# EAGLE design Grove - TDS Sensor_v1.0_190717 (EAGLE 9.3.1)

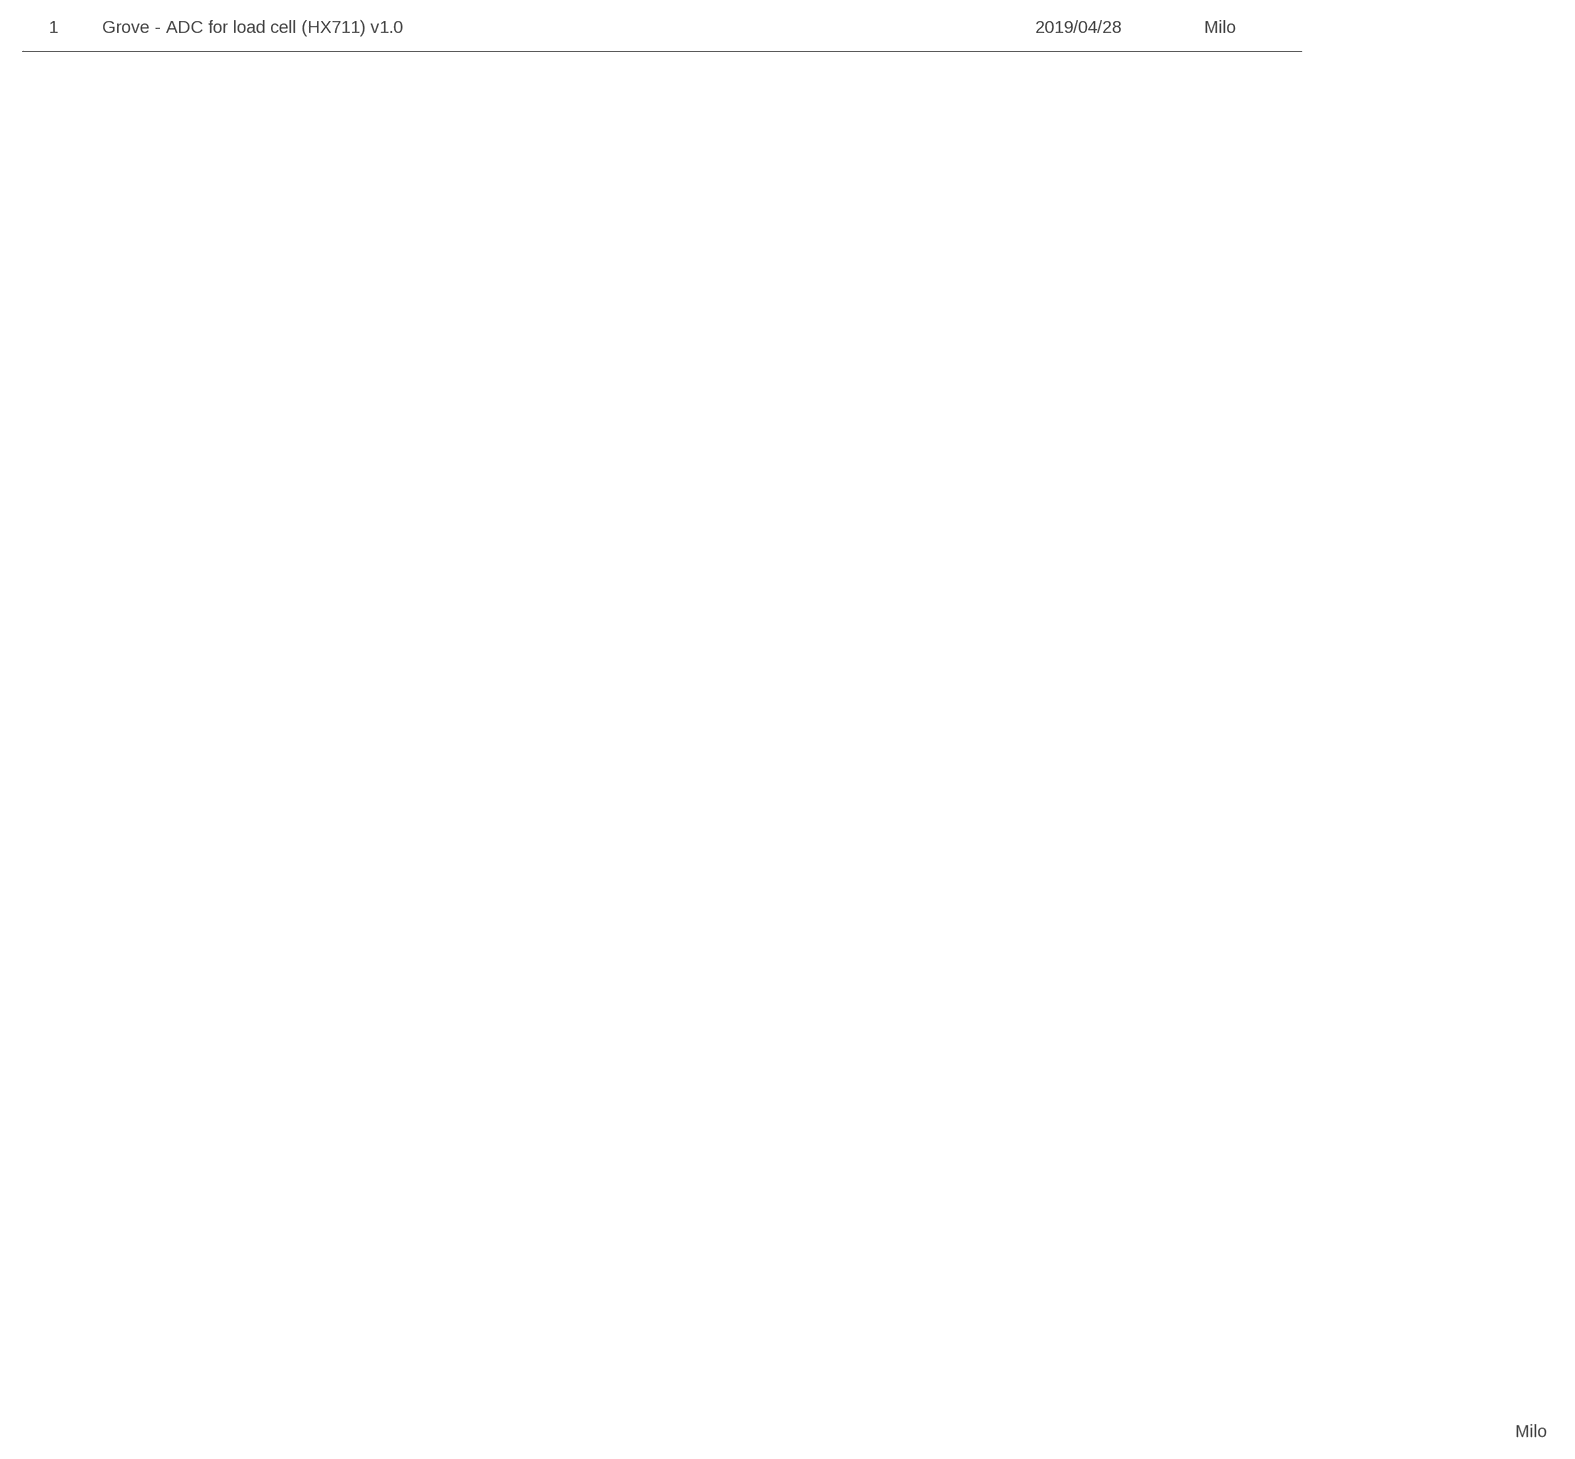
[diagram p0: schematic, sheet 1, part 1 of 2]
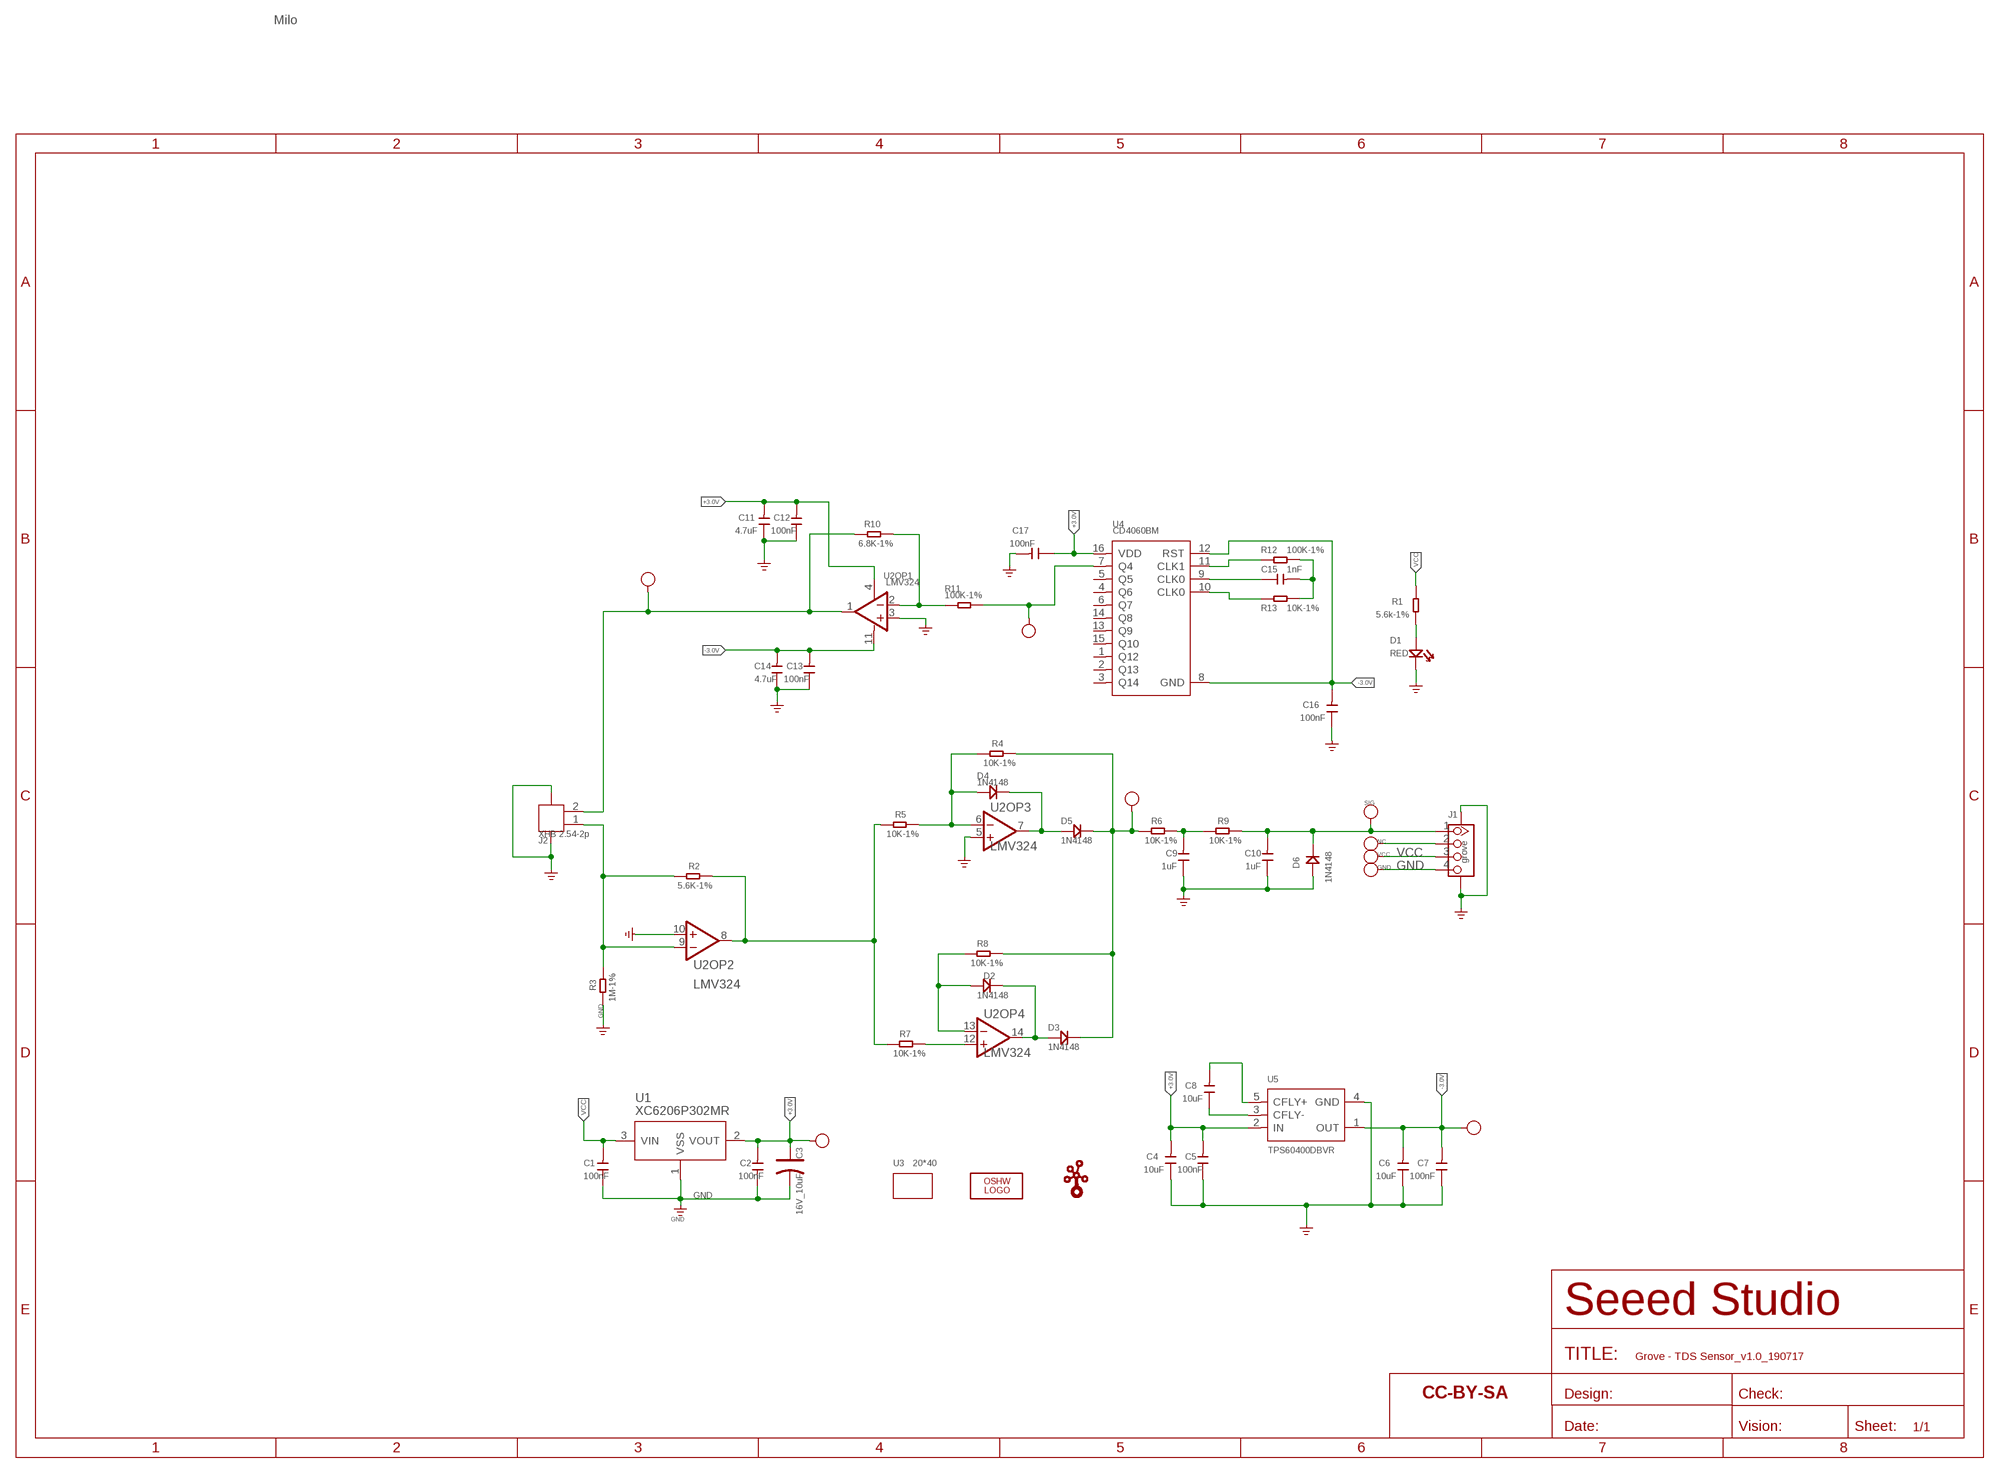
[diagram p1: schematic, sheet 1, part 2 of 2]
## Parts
+3.0V  +3.0V  PAD-TEST-POINT'4545'  [TP_4545]
-3.0V  TP2  PAD-TEST-POINT'4545'  [TP_4545]
C1  100nF  CAP-0402  [C0402]
C2  100nF  CAP-0402  [C0402]
C3  16V_10uF  CAP-POLAR-AVX-A  [AVX-A]
C4  10uF  CAP-0402  [C0402]
C5  100nF  CAP-0402  [C0402]
C6  10uF  CAP-0402  [C0402]
C7  100nF  CAP-0402  [C0402]
C8  10uF  CAP-0402  [C0402]
C9  1uF  CAP-0402  [C0402]
C10  1uF  CAP-0402  [C0402]
C11  4.7uF  CAP-0402  [C0402]
C12  100nF  CAP-0402  [C0402]
C13  100nF  CAP-0402  [C0402]
C14  4.7uF  CAP-0402  [C0402]
C15  1nF  CAP-0402  [C0402]
C16  100nF  CAP-0402  [C0402]
C17  100nF  CAP-0402  [C0402]
D1  RED  LED-0402  [LED-0402]
D2  1N4148  DIODE'0603'  [SOD-523]
D3  1N4148  DIODE'0603'  [SOD-523]
D4  1N4148  DIODE'0603'  [SOD-523]
D5  1N4148  DIODE'0603'  [SOD-523]
D6  1N4148  DIODE'0603'  [SOD-523]
GND  DNP  PAD-TEST-POINT'4545'  [TP_4545]
J1  grove  GROVE-CONNECTOR-SMD-320110030  [HW4-SMD-2.0]
J2  XHB 2.54-2p  JST-2P-SMD-2.5  [HW2-SMD-2.5-10X10X6MM]
LOGO1  LOGO-OSHW-FILLX0150-NT  [OSHW_FILLX150_NOTEXT]
NC  DNP  PAD-TEST-POINT'4545'  [TP_4545]
R1  5.6k-1%  RES-0402  [R0402]
R2  5.6K-1%  RES-0402  [R0402]
R3  1M-1%  RES-0402  [R0402]
R4  10K-1%  RES-0402  [R0402]
R5  10K-1%  RES-0402  [R0402]
R6  10K-1%  RES-0402  [R0402]
R7  10K-1%  RES-0402  [R0402]
R8  10K-1%  RES-0402  [R0402]
R9  10K-1%  RES-0402  [R0402]
R10  6.8K-1%  RES-0402  [R0402]
R11  100K-1%  RES-0402  [R0402]
R12  100K-1%  RES-0402  [R0402]
R13  10K-1%  RES-0402  [R0402]
SIG  DNP  PAD-TEST-POINT'4545'  [TP_4545]
TP3  TP2  PAD-TEST-POINT'4545'  [TP_4545]
TP4  TP2  PAD-TEST-POINT'4545'  [TP_4545]
TP5  TP2  PAD-TEST-POINT'4545'  [TP_4545]
U1  XC6206P302MR  XC6206MR  [SOT23]
U2  LMV324  AMPLIFIER-LMV324-310020019  [SOIC14-1.27-9.3X4.3MM]
U3  20*40  GROVE-1X2-TOP  [GROVE-1*2-TEST-PLATFORM-TOP]
U4  CD4060BM  CONTROLLER-CD4060BM  [SOIC16-1.27-10X3.9MM]
U5  TPS60400DBVR  PMIC-TPS60400DBVR  [SOT-23-5]
U$2  LOGO-GROVE  [GROVE-SILK-BIG]
VCC  DNP  PAD-TEST-POINT'4545'  [TP_4545]

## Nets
+3.0V: +3.0V.T C2.2 C3.+ C4.2 C5.2 C11.2 C12.2 C17.1 U1.2(VOUT) U2.4(OP1:V+) U4.16(VDD) U5.2(IN)
-3.0V: -3.0V.T C6.2 C7.2 C13.2 C14.2 C16.2 U2.11(OP1:V-) U4.8(GND) U4.12(RST) U5.1(OUT)
GND: C1.1 C2.1 C3.- C4.1 C5.1 C6.1 C7.1 C9.1 C10.1 C11.1 C12.1 C13.1 C14.1 C16.1 C17.2 D1.- D6.+ GND.T J1.4 J1.SS1 J1.SS2 J2.3 J2.4 R3.2 U1.1(VSS) U2.3(OP1:IN+) U2.5(OP3:IN+) U2.10(OP2:IN+) U5.4(GND) ; supply symbol labelled GND_POWER
N$1: D1.+ R1.1
N$2: J2.1 R2.2 R3.1 U2.9(OP2:IN-)
N$3: D4.+ R4.2 R5.1 U2.6(OP3:IN-)
N$4: D3.- D5.- R4.1 R6.1 R8.2 TP5.T
N$5: J1.2 NC.T
N$6: C9.2 R6.2 R9.2
N$7: D4.- D5.+ U2.7(OP3:OUT)
N$8: R7.2 U2.12(OP4:IN+)
N$9: D2.+ R8.1 U2.13(OP4:IN-)
N$10: D2.- D3.+ U2.14(OP4:OUT)
N$11: R10.1 R11.1 U2.2(OP1:IN-)
N$12: R2.1 R5.2 R7.1 U2.8(OP2:OUT)
N$13: J2.2 R10.2 TP4.T U2.1(OP1:OUT)
N$14: C10.2 D6.- J1.1 R9.1 SIG.T
N$15: C8.1 U5.3(CFLY-)
N$16: C8.2 U5.5(CFLY+)
N$17: R12.1 U4.11(CLK1)
N$18: C15.1 U4.9(CLK0)
N$19: R13.1 U4.10(CLK0)
N$20: C15.2 R12.2 R13.2
N$21: R11.2 TP3.T U4.7(Q4)
VCC: C1.2 J1.3 R1.2 U1.3(VIN) VCC.T
Unconnected: U4.1(Q12) U4.2(Q13) U4.3(Q14) U4.4(Q6) U4.5(Q5) U4.6(Q7) U4.13(Q9) U4.14(Q8) U4.15(Q10)

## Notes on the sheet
- 1 | Grove - ADC for load cell (HX711) v1.0 | 2019/04/28 | Milo
- Milo
- Milo

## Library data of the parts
+3.0V -3.0V GND NC SIG TP3-TP5 VCC = Discrete:PAD-TEST-POINT; PARTNO: DNP
C1 C2 C4-C17 = Discrete-new:CAP: Ceramic Capacitors
C3 = Discrete-new:CAP-POLAR: Electrolytic Capacitors,Tantalum Capacitors and Super Capacitors
D1 = Discrete-new:LED
D2-D6 = Discrete-new:DIODE
J1 = Connector-new:GROVE-CONNECTOR-SMD
J2 = Connector-new:JST-2P-SMD
LOGO1 = logo:LOGO-OSHW-FILL; PARTNO: DNP
R1-R13 = Discrete-new:RES
U1 = IC:XC6206: LOW ESR Cap.Compatible Positive Voltage Regulators
U2 = IC-new:AMPLIFIER-LMV324
U3 = moudle-new:GROVE
U4 = IC-new:CONTROLLER-CD4060BM
U5 = IC-new:PMIC-TPS60400DBVR
U$2 = logo:LOGO-GROVE; PARTNO: DNP

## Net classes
3 usbvcc: width 0.508 mm, drill 0.61 mm, clearance 0.254 mm

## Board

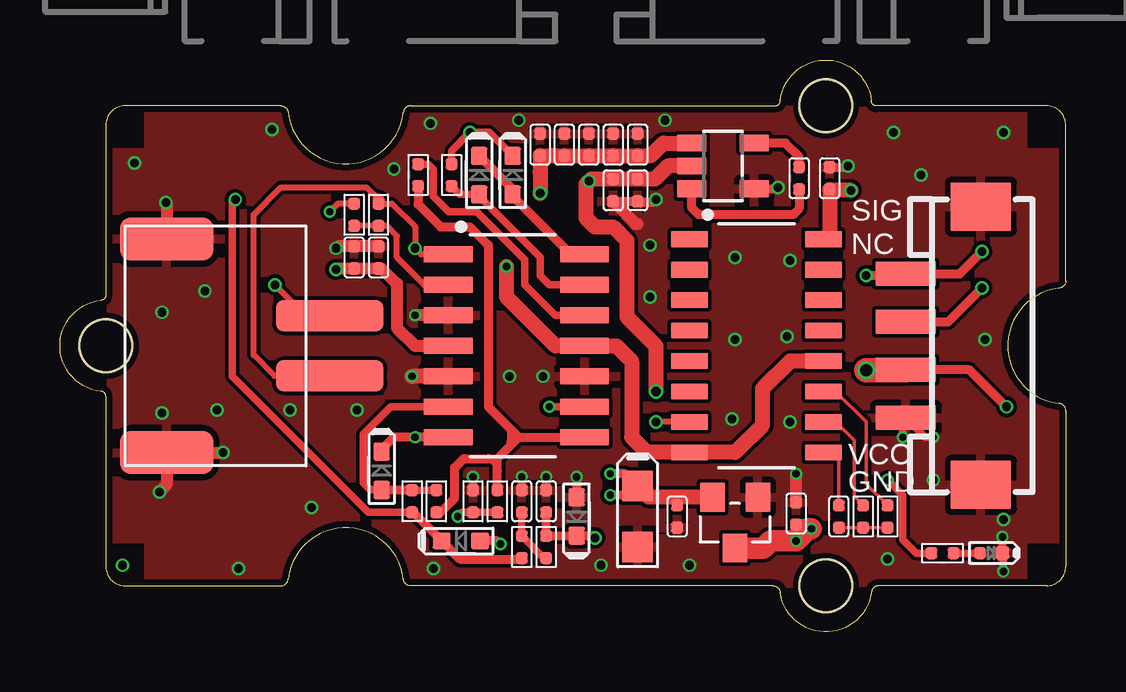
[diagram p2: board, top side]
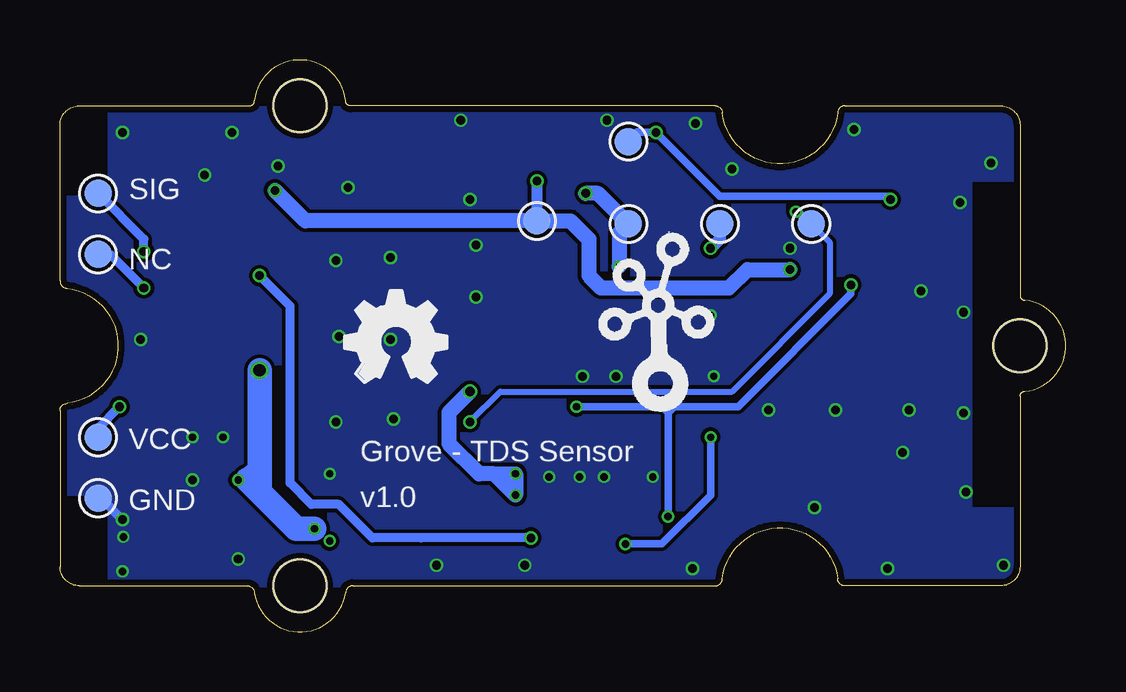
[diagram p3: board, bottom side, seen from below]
Size 41.91 x 23.83 mm. Coordinates in mm from the lower left corner, seen from the top.
Copper layers (1*16): Top 0.035mm / dielectric 1.5mm / Bottom 0.035mm
Design rules "SeeedStudio_2layer_DRU_no_angle_20140221": minimum track width 1mil, minimum drill 10mil, track to track 6mil, track to pad 6mil, pad to pad 6mil, via to via 6mil, smd to smd 0mil, copper to edge 10mil, drill to drill 10mil, minimum pad ring 4mil, minimum via ring 4mil, stop-mask expansion 2mil, vias tented up to drill 25mil, thermal gap 10mil

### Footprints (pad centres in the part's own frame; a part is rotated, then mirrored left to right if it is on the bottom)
TP_4545 = smd 1.143 x 1.143: T 0,0
C0402 = smd 0.5 x 0.5: 1 -0.463,0; 2 0.463,0
AVX-A = smd 1.27 x 1.27: + 1.27,0; - -1.27,0
LED-0402 = smd 0.5 x 0.5: + 0.463,0 | smd 0.58 x 0.58: - -0.468,0
SOD-523 = smd 0.762 x 0.7: + 0.8,0; - -0.8,0
HW4-SMD-2.0 = smd 1 x 2.5: 1 -3,0; 2 -1,0; 3 1,0; 4 3,0 | smd 2 x 2.5: SS1 -5.8,3.123; SS2 5.8,3.123
HW2-SMD-2.5-10X10X6MM = smd 1.3 x 4.5: 1 -1.25,0; 2 1.25,0 | smd 1.8 x 3.9: 3 -4.45,-6.8; 4 4.45,-6.8
R0402 = smd 0.5 x 0.5: 1 -0.463,0; 2 0.463,0
SOT23 = smd 1.016 x 1.2: 1 -0.95,-1.06; 2 0.95,-1.06; 3 0,1.06
SOIC14-1.27-9.3X4.3MM = smd 0.66 x 2.032: 1 -3.81,-2.68; 2 -2.54,-2.68; 3 -1.27,-2.68; 4 0,-2.68; 5 1.27,-2.68; 6 2.54,-2.68; 7 3.81,-2.68; 8 3.81,2.997; 9 2.54,2.997; 10 1.27,2.997; 11 0,2.997; 12 -1.27,2.997; 13 -2.54,2.997; 14 -3.81,2.997
GROVE-1*2-TEST-PLATFORM-TOP = hole 2.2: 10.635,10; 10.635,-10; -19.365,0
SOIC16-1.27-10X3.9MM = smd 0.66 x 1.524: 1 -4.445,-2.794; 2 -3.175,-2.794; 3 -1.905,-2.794; 4 -0.635,-2.794; 5 0.635,-2.794; 6 1.905,-2.794; 7 3.175,-2.794; 8 4.445,-2.794; 9 4.445,2.794; 10 3.175,2.794; 11 1.905,2.794; 12 0.635,2.794; 13 -0.635,2.794; 14 -1.905,2.794; 15 -3.175,2.794; 16 -4.445,2.794
SOT-23-5 = smd 0.69 x 1.2: 1 -0.95,-1.3; 2 0,-1.3; 3 0.95,-1.3; 4 0.95,1.3; 5 -0.95,1.3

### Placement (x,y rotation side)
+3.0V  22.04,17.13 0 bottom
-3.0V  18.23,17 0 bottom
C1  30.67,4.94 270 top
C2  25.72,4.81 90 top
C3  24.07,4.81 90 top
C4  23.05,18.4 90 top
C5  24.07,18.4 90 top
C6  23.05,20.3 270 top
C7  24.07,20.3 270 top
C8  30.8,18.91 90 top
C9  19.24,5.44 270 top
C10  20.26,5.44 270 top
C11  12.26,15.6 270 top
C12  32.07,18.91 270 top
C13  21.02,20.3 270 top
C14  20,20.3 270 top
C15  32.45,4.81 270 top
C16  22.04,20.3 270 top
C17  13.27,15.6 90 top
D1  38.8,3.29 180 top
D2  17.46,19.03 270 top
D3  18.86,19.03 270 top
D4  13.4,6.71 270 top
D5  16.7,3.79 0 top
D6  21.53,4.81 90 top
GND  40.32,5.57 0 bottom
J1  35.24,11.92 270 top
J2  11.24,11.92 270 top
LOGO1  30.04,10.4 0 bottom
NC  40.32,15.73 0 bottom
R1  36.77,3.29 180 top
R2  18.23,5.44 270 top
R3  17.21,5.44 90 top
R4  14.67,5.44 90 top
R5  15.69,5.44 270 top
R6  19.24,3.54 90 top
R7  14.92,19.03 90 top
R8  16.32,19.03 90 top
R9  20.26,3.54 270 top
R10  13.27,17.38 90 top
R11  12.26,17.38 90 top
R12  34.48,4.81 270 top
R13  33.47,4.81 270 top
SIG  40.32,18.27 0 bottom
TP3  10.61,17 0 bottom
TP4  14.42,17 0 bottom
TP5  18.23,20.43 0 bottom
U1  28.13,4.56 180 top
U2  18.86,11.92 270 top
U3  21.27,11.92 0 top
U4  29.02,11.92 270 top
U5  27.62,19.41 270 top
U$2  16.96,10.14 0 bottom
VCC  40.32,8.11 0 bottom

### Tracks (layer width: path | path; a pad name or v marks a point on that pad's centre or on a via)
+3.0V  (via drill 0.3, 0.36, 0.41)
  Top 0.305: C2.2 25.72,5.62
  Top 0.381: v22.92,5.7 23.69,5.7 C3.+ 24.53,5.62 | 23.56,6.59 v22.92,6.59
  Top 0.457: 22.12,18.86 v22.04,18.78
  Top 0.508: U2.4 14.8,11.92 14.03,12.68 14.03,14.51 13.4,15.14 C17.1 C11.2 11.54,15.14 v11.49,15.1
  Top 0.635: U1.2 25.72,5.62 24.53,5.62 | U5.2 25.34,19.41 24.78,18.86 C5.2 C4.2 22.12,18.86 | v32.96,18.4 32.11,18.4 C12.2 32.07,16.62 U4.16 | v22.04,18.78 21.91,18.65 21.91,17.26 22.29,16.87 23.05,16.87 23.62,16.3 23.62,13.13 24.83,11.92 v24.83,10.02
  Bottom 0.457: v22.04,18.78 +3.0V.T
  Bottom 0.635: v32.96,18.4 31.69,17.13 +3.0V.T 20.64,17.13 19.88,16.37 19.88,14.84 19.37,14.33 14.03,14.33 13.27,15.1 v11.49,15.1 | v24.83,10.02 25.71,9.14 25.71,7.84 24.45,6.59 23.81,6.59 | 23.81,6.59 v22.92,5.7 v22.92,6.59 23.81,6.59
-3.0V  (via drill 0.3, 0.38)
  Top 0.152: 20,19.16 20.51,19.67 20.51,19.84
  Top 0.635: U4.12 30.42,11.29 29.27,10.14 29.27,8.62 28.13,7.48 U4.8 24.45,7.48 23.81,8.11 23.81,11.29 23.18,11.92 U2.11 20.64,11.92 18.61,13.95 v18.61,15.22 | U5.1 25.14,20.36 24.62,19.84 C7.2 C6.2 C16.2 C13.2 20.51,19.84 C14.2 20,19.16 v20,18.27
  Bottom 0.635: v18.61,15.22 18.61,16.62 -3.0V.T 19.5,18.27 v20,18.27
GND  (via drill 0.3, 0.36)
  Top 0.305: v39.27,3.96 D1.- 39.31,3.24 v39.31,2.52 | v35.12,8.11 35.12,8.79 J1.4 36.05,8.11 v36.39,8.11 | C10.1 v20.26,6.46 | C9.1 v19.24,6.46 | R3.2 v17.21,6.46
  Top 0.381: v21.53,6.46 D6.+ | U5.4 29.85,18.46 v29.91,18.53 | C12.1 32.78,19.37 v32.83,19.41 | v24.83,18.02 24.7,17.89 24.11,17.89 C5.1 C4.1
  Top 0.508: C1.1 v30.67,6.59 | v11.49,15.99 11.58,16.07 C11.1 C17.2 | v4.41,17.89 4.44,17.86 J2.3 | v4.15,5.83 4.13,5.83 4.44,6.14 J2.4 v6.79,7.47 v6.8,7.48 | C4.1 23.99,17 24.07,17 | U2.3 v14.8,13.19
  Top 0.635: U2.5 v14.67,10.65
  Bottom 0.381: GND.T 40.2,5.57 v39.31,4.68
  other vias: 24.58,16.11 24.58,13.95 20.13,10.65 18.73,10.65 28.13,12.18 28.13,15.6 30.42,15.48 30.42,8.75 35.88,19.03 34.74,20.81 39.31,20.81 38.55,12.18 36.39,6.33 34.48,3.03 26.23,2.78 22.54,2.78 15.56,2.65 10.48,5.19 7.43,2.65 2.6,2.78 4.26,9.13 4.26,13.32 3.11,19.54 8.83,20.94 13.91,19.29 15.43,21.19 25.21,21.32 19.11,21.32 6.54,9.25 6.03,14.21 28,8.87 30.29,12.3 9.59,9.25 12.38,9.25
  pour Bottom: -1.21,25.64 43.5,25.64 43.5,-0.4 -1.21,-0.4
  pour Top: -1.21,25.64 43.63,25.64 43.63,-0.4 0.83,-0.4 0.83,-1.67 -1.21,-1.67
N$1
  Top 0.305: R1.1 D1.+
N$2  (via drill 0.3, 0.36)
  Top 0.254: J2.1 10.24,13.17 v8.95,14.46
  Top 0.305: R2.2 R3.1 16.75,4.98 v16.57,4.81 | v20.38,9.38 U2.9 | 11.22,13.19 J2.1
  Bottom 0.305: v16.57,4.81 16.57,9.13 | 16.57,9.13 16.83,9.38 | 16.83,9.38 v20.38,9.38 | 16.83,9.38 16.32,9.38 | 16.32,9.38 13.65,9.38 8.95,14.08 v8.95,14.46 | 16.57,9.13 16.32,9.38
N$3
  Top 0.305: R5.1 R4.2 | U2.6 13.78,9.38 12.64,8.24 12.64,6.21 12.93,5.91 D4.+
  Top 0.381: D4.+ R4.2
N$4  (via drill 0.36)
  Top 0.305: R8.2 16.32,20.05 v17.08,20.81 17.88,20.81 D3.- | R4.1 12.85,4.98 7.18,10.65 7.18,17.89 v7.3,18.02
  Top 0.381: R4.1 14.71,4.98 D5.- 16.66,3.03 19.2,3.03 R6.1
  Bottom 0.305: 17.84,20.81 v17.08,20.81 14.42,18.14 7.43,18.14 v7.3,18.02
  Bottom 0.381: 17.84,20.81 TP5.T
N$5  (via drill 0.36)
  Top 0.381: J1.2 37.01,12.92 v38.42,14.33
  Bottom 0.381: NC.T 39.82,15.73 v38.42,14.33
N$6
  Top 0.305: C9.2 R6.2 20.17,3.08 R9.2
N$7  (via drill 0.3)
  Top 0.381: v18.35,3.67 18.23,3.79 D5.+ | U2.7 v14.8,8.11 13.91,8.11 13.4,7.6 D4.-
  Bottom 0.305: v18.35,3.67 16.83,3.67 14.8,5.7 v14.8,8.11
N$8
  Top 0.305: R7.2 15.35,19.5 15.56,19.29 15.56,18.14 16.21,17.5 17.37,17.5 19.37,15.5 19.37,14.46 20.64,13.19 U2.12
N$9
  Top 0.305: U2.13 20.38,14.46 20,14.84 20,15.6 17.46,18.14 D2.+ 16.66,18.23 R8.1
  Top 0.381: D2.+ 17.5,18.23
N$10
  Top 0.381: D2.- 18.86,18.44 D3.+ 18.86,18.14 21.27,15.73 U2.14
N$11
  Top 0.254: U2.2 15.18,14.46 14.03,15.6 14.03,16.49 13.61,16.92 R10.1 R11.1
N$12
  Top 0.152: 17.84,7.22 18.23,6.84 18.23,6.71
  Top 0.381: R5.2 15.86,4.98 16.45,5.57 16.45,6.84 16.83,7.22 17.84,7.22 18.23,7.22 | R2.1 18.23,6.71 18.23,7.22 | 18.23,7.22 18.86,7.86 | 18.86,7.86 19.11,8.11 | 19.11,8.11 U2.8 | R7.1 14.92,17.81 15.86,16.87 17.08,16.87 17.84,16.11 17.84,9.38 18.8,8.43 | 18.8,8.43 19.11,8.11 | 18.8,8.43 18.8,7.92 18.86,7.86
N$13  (via drill 0.36)
  Top 0.254: 13.27,18.02 12.76,18.53 9.21,18.53 8.07,17.38 8.07,11.54 8.93,10.67 J2.2 | R10.2 13.83,17.84 14.8,16.87 v14.8,15.99 15.05,15.73 U2.1
  Top 0.508: 13.27,18.02 R10.2 | 15.81,15.73 U2.1
  Bottom 0.508: TP4.T 14.42,16.37 v14.8,15.99
N$14  (via drill 0.36)
  Top 0.381: C10.2 R9.1 D6.- 22.2,4.01 v22.29,3.92 | v33.59,14.84 35.16,14.84 J1.1 37.48,14.92 v38.42,15.86
  Bottom 0.381: v22.29,3.92 26.86,3.92 28.89,3.92 30.29,5.32 31.43,5.32 32.32,6.21 32.32,13.57 v33.59,14.84 | v38.42,15.86 38.42,16.37 SIG.T
N$15
  Top 0.381: C8.1 30.8,17.64 30.54,17.38 26.61,17.38 26.32,17.67 U5.3
N$16
  Top 0.381: C8.2 30.8,19.8 30.23,20.36 U5.5
N$17
  Top 0.152: R12.1 33.59,6.16 33.59,8.75 32.32,10.02 U4.11
N$18
  Top 0.152: U4.9 31.94,7.35 32.45,7.35 C15.1
N$19
  Top 0.152: R13.1 33.08,5.65 33.08,7.98 32.32,8.75 U4.10
N$20
  Top 0.152: R12.2 R13.2 C15.2
N$21  (via drill 0.3, 0.36)
  Top 0.254: R11.2 11.58,17.84 v11.24,17.51 | U4.7 v24.83,8.75
  Bottom 0.254: v11.24,17.51 11.11,17.51 TP3.T 9.84,16.24 9.84,14.08 13.91,10.02 23.56,10.02 v24.83,8.75
VCC  (via drill 0.3, 0.36, 0.51)
  Top 0.305: v34.48,6.33 35.12,5.7 35.12,3.84 35.67,3.29 R1.2
  Top 0.381: J1.3 37.89,10.92 v39.43,9.38
  Top 0.508: v31.31,4.3 31.13,4.47 C1.2 v30.67,3.79
  Top 0.889: U1.3 29.31,3.5 29.61,3.79 v30.67,3.79 31.18,4.3 v31.31,4.3
  Top 1.016: v33.59,10.91 35.23,10.91 J1.3
  Bottom 0.305: 34.1,6.33 v34.48,6.33
  Bottom 0.381: v39.43,9.38 40.32,8.49 VCC.T | 33.59,7.22 v34.48,6.33
  Bottom 1.016: 33.59,6.08 33.59,7.22 v33.59,10.91 | 34.1,6.33 32.07,4.3 v31.31,4.3

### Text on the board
tNames: SIG | NC | VCC | GND
bNames: SIG | NC | Grove - TDS Sensor | VCC | v1.0 | GND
